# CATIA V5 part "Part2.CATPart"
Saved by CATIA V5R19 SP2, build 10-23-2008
Part number: Part2
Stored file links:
  D:\BEHROOZ mashin\tarh haye mashin\hb\Part2.CATPart

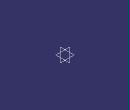
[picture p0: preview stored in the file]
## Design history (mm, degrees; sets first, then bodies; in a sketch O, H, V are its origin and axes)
Body1 (main body)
